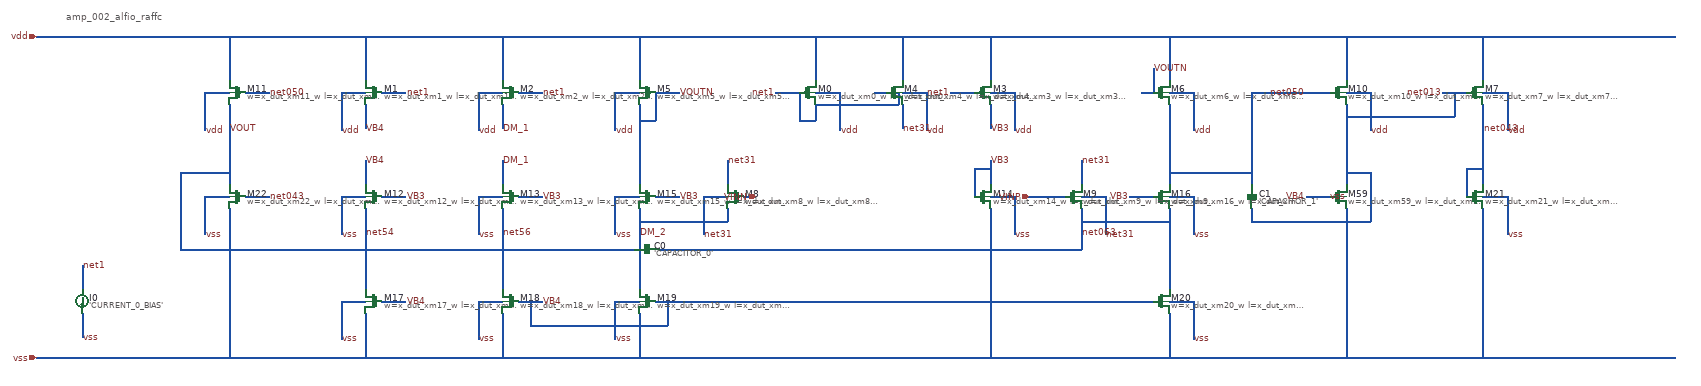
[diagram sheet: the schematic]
v {xschem version=3.4.6 file_version=1.2}
G {}
K {}
V {}
S {}
E {}
T {amp_002_alfio_raffc} -1785 -200 0 0 0.4 0.4 {}
C {devices/capa_np.sym} -340 390 1 0 {name=C0 value='CAPACITOR_0'}
C {devices/capa_np.sym} 1165 260 0 0 {name=C1 value='CAPACITOR_1'}
C {devices/isource_np.sym} -1745 520 0 0 {name=I0 value='CURRENT_0_BIAS'}
C {devices/sg13_lv_pmos_np.sym} 60 0 0 0 {name=M0 model=sg13_lv_pmos spiceprefix=X w=x_dut_xm0_w l=x_dut_xm0_l m=x_dut_xm0_m}
C {devices/sg13_lv_pmos_np.sym} -1020 0 0 1 {name=M1 model=sg13_lv_pmos spiceprefix=X w=x_dut_xm1_w l=x_dut_xm1_l m=x_dut_xm1_m}
C {devices/sg13_lv_pmos_np.sym} 1380 0 0 0 {name=M10 model=sg13_lv_pmos spiceprefix=X w=x_dut_xm10_w l=x_dut_xm10_l m=x_dut_xm10_m}
C {devices/sg13_lv_pmos_np.sym} -1360 0 0 1 {name=M11 model=sg13_lv_pmos spiceprefix=X w=x_dut_xm11_w l=x_dut_xm11_l m=x_dut_xm11_m}
C {devices/sg13_lv_nmos_np.sym} -1020 260 0 1 {name=M12 model=sg13_lv_nmos spiceprefix=X w=x_dut_xm12_w l=x_dut_xm12_l m=x_dut_xm12_m}
C {devices/sg13_lv_nmos_np.sym} -680 260 0 1 {name=M13 model=sg13_lv_nmos spiceprefix=X w=x_dut_xm13_w l=x_dut_xm13_l m=x_dut_xm13_m}
C {devices/sg13_lv_nmos_np.sym} 495 260 0 0 {name=M14 model=sg13_lv_nmos spiceprefix=X w=x_dut_xm14_w l=x_dut_xm14_l m=x_dut_xm14_m}
C {devices/sg13_lv_nmos_np.sym} -340 260 0 1 {name=M15 model=sg13_lv_nmos spiceprefix=X w=x_dut_xm15_w l=x_dut_xm15_l m=x_dut_xm15_m}
C {devices/sg13_lv_nmos_np.sym} 940 260 0 0 {name=M16 model=sg13_lv_nmos spiceprefix=X w=x_dut_xm16_w l=x_dut_xm16_l m=x_dut_xm16_m}
C {devices/sg13_lv_nmos_np.sym} -1020 520 0 1 {name=M17 model=sg13_lv_nmos spiceprefix=X w=x_dut_xm17_w l=x_dut_xm17_l m=x_dut_xm17_m}
C {devices/sg13_lv_nmos_np.sym} -680 520 0 1 {name=M18 model=sg13_lv_nmos spiceprefix=X w=x_dut_xm18_w l=x_dut_xm18_l m=x_dut_xm18_m}
C {devices/sg13_lv_nmos_np.sym} -340 520 0 1 {name=M19 model=sg13_lv_nmos spiceprefix=X w=x_dut_xm19_w l=x_dut_xm19_l m=x_dut_xm19_m}
C {devices/sg13_lv_pmos_np.sym} -680 0 0 1 {name=M2 model=sg13_lv_pmos spiceprefix=X w=x_dut_xm2_w l=x_dut_xm2_l m=x_dut_xm2_m}
C {devices/sg13_lv_nmos_np.sym} 940 520 0 0 {name=M20 model=sg13_lv_nmos spiceprefix=X w=x_dut_xm20_w l=x_dut_xm20_l m=x_dut_xm20_m}
C {devices/sg13_lv_nmos_np.sym} 1720 260 0 0 {name=M21 model=sg13_lv_nmos spiceprefix=X w=x_dut_xm21_w l=x_dut_xm21_l m=x_dut_xm21_m}
C {devices/sg13_lv_nmos_np.sym} -1360 260 0 1 {name=M22 model=sg13_lv_nmos spiceprefix=X w=x_dut_xm22_w l=x_dut_xm22_l m=x_dut_xm22_m}
C {devices/sg13_lv_pmos_np.sym} 495 0 0 0 {name=M3 model=sg13_lv_pmos spiceprefix=X w=x_dut_xm3_w l=x_dut_xm3_l m=x_dut_xm3_m}
C {devices/sg13_lv_pmos_np.sym} 275 0 0 0 {name=M4 model=sg13_lv_pmos spiceprefix=X w=x_dut_xm4_w l=x_dut_xm4_l m=x_dut_xm4_m}
C {devices/sg13_lv_pmos_np.sym} -340 0 0 1 {name=M5 model=sg13_lv_pmos spiceprefix=X w=x_dut_xm5_w l=x_dut_xm5_l m=x_dut_xm5_m}
C {devices/sg13_lv_nmos_np.sym} 1380 260 0 0 {name=M59 model=sg13_lv_nmos spiceprefix=X w=x_dut_xm59_w l=x_dut_xm59_l m=x_dut_xm59_m}
C {devices/sg13_lv_pmos_np.sym} 940 0 0 0 {name=M6 model=sg13_lv_pmos spiceprefix=X w=x_dut_xm6_w l=x_dut_xm6_l m=x_dut_xm6_m}
C {devices/sg13_lv_pmos_np.sym} 1720 0 0 0 {name=M7 model=sg13_lv_pmos spiceprefix=X w=x_dut_xm7_w l=x_dut_xm7_l m=x_dut_xm7_m}
C {devices/sg13_lv_pmos_np.sym} -120 260 0 1 {name=M8 model=sg13_lv_pmos spiceprefix=X w=x_dut_xm8_w l=x_dut_xm8_l m=x_dut_xm8_m}
C {devices/sg13_lv_pmos_np.sym} 720 260 0 0 {name=M9 model=sg13_lv_pmos spiceprefix=X w=x_dut_xm9_w l=x_dut_xm9_l m=x_dut_xm9_m}
N -1745 430 -1745 490 {}
N -1745 550 -1745 610 {}
N -1500 200 -1500 390 {}
N -1440 0 -1440 94 {}
N -1440 260 -1440 354 {}
N -1380 -140 -1380 -30 {}
N -1380 30 -1380 230 {}
N -1380 290 -1380 660 {}
N -1100 0 -1100 94 {}
N -1100 260 -1100 354 {}
N -1100 520 -1100 614 {}
N -1040 -140 -1040 -30 {}
N -1040 30 -1040 90 {}
N -1040 170 -1040 230 {}
N -1040 290 -1040 490 {}
N -1040 550 -1040 660 {}
N -760 0 -760 94 {}
N -760 260 -760 354 {}
N -760 520 -760 614 {}
N -700 -140 -700 -30 {}
N -700 30 -700 90 {}
N -700 170 -700 230 {}
N -700 290 -700 490 {}
N -700 550 -700 660 {}
N -630 520 -630 580 {}
N -420 0 -420 94 {}
N -420 260 -420 354 {}
N -420 520 -420 614 {}
N -360 -140 -360 -30 {}
N -360 30 -360 230 {}
N -360 290 -360 490 {}
N -360 550 -360 660 {}
N -320 0 -320 70 {}
N -290 520 -290 580 {}
N -200 260 -200 354 {}
N -140 170 -140 230 {}
N -140 290 -140 320 {}
N 40 0 40 70 {}
N 80 -140 80 -30 {}
N 80 30 80 70 {}
N 140 0 140 94 {}
N 285 0 285 30 {}
N 295 -140 295 -30 {}
N 295 30 295 90 {}
N 355 0 355 94 {}
N 475 190 475 260 {}
N 515 -140 515 -30 {}
N 515 30 515 90 {}
N 515 170 515 230 {}
N 515 290 515 660 {}
N 575 0 575 94 {}
N 575 260 575 354 {}
N 740 170 740 230 {}
N 740 290 740 390 {}
N 800 260 800 354 {}
N 920 -60 920 0 {}
N 960 -140 960 -30 {}
N 960 30 960 230 {}
N 960 290 960 490 {}
N 960 550 960 660 {}
N 1020 0 1020 94 {}
N 1020 260 1020 354 {}
N 1020 520 1020 614 {}
N 1165 0 1165 230 {}
N 1165 290 1165 320 {}
N 1400 -140 1400 -30 {}
N 1400 30 1400 230 {}
N 1400 290 1400 660 {}
N 1460 0 1460 94 {}
N 1460 200 1460 320 {}
N 1670 0 1670 60 {}
N 1700 190 1700 260 {}
N 1740 -140 1740 -30 {}
N 1740 30 1740 230 {}
N 1740 290 1740 660 {}
N 1800 0 1800 94 {}
N 1800 260 1800 354 {}
N -1860 -140 2220 -140 {}
N -1440 0 -1380 0 {}
N -1340 0 -1280 0 {}
N -1100 0 -1040 0 {}
N -1000 0 -940 0 {}
N -760 0 -700 0 {}
N -660 0 -600 0 {}
N -420 0 -360 0 {}
N -320 0 -260 0 {}
N -20 0 40 0 {}
N 80 0 140 0 {}
N 225 0 285 0 {}
N 295 0 355 0 {}
N 415 0 475 0 {}
N 515 0 575 0 {}
N 890 0 920 0 {}
N 960 0 1020 0 {}
N 1165 0 1360 0 {}
N 1400 0 1460 0 {}
N 1640 0 1700 0 {}
N 1740 0 1800 0 {}
N 80 30 285 30 {}
N 1400 60 1670 60 {}
N -360 70 -320 70 {}
N 40 70 80 70 {}
N 475 190 515 190 {}
N 1700 190 1740 190 {}
N -1500 200 -1380 200 {}
N 960 200 1165 200 {}
N 1400 200 1460 200 {}
N -1440 260 -1380 260 {}
N -1340 260 -1280 260 {}
N -1100 260 -1040 260 {}
N -1000 260 -940 260 {}
N -760 260 -700 260 {}
N -660 260 -600 260 {}
N -420 260 -360 260 {}
N -320 260 -260 260 {}
N -200 260 -140 260 {}
N -100 260 -70 260 {}
N 515 260 575 260 {}
N 610 260 700 260 {}
N 740 260 800 260 {}
N 860 260 920 260 {}
N 960 260 1020 260 {}
N 1300 260 1360 260 {}
N 1740 260 1800 260 {}
N -360 320 -140 320 {}
N 740 320 960 320 {}
N 1165 320 1460 320 {}
N -1500 390 -370 390 {}
N -310 390 740 390 {}
N -1100 520 -1040 520 {}
N -1000 520 -940 520 {}
N -760 520 -700 520 {}
N -660 520 -600 520 {}
N -420 520 -360 520 {}
N -320 520 920 520 {}
N 960 520 1020 520 {}
N -630 580 -290 580 {}
N -1860 660 2220 660 {}
C {devices/lab_wire.sym} -700 90 2 0 {name=l0 lab=DM_1}
C {devices/lab_wire.sym} -700 170 0 1 {name=l1 lab=DM_1}
C {devices/lab_wire.sym} -360 350 2 0 {name=l2 lab=DM_2}
C {devices/lab_wire.sym} -940 260 0 1 {name=l3 lab=VB3}
C {devices/lab_wire.sym} -600 260 0 1 {name=l4 lab=VB3}
C {devices/lab_wire.sym} -260 260 0 1 {name=l5 lab=VB3}
C {devices/lab_wire.sym} 515 170 0 1 {name=l6 lab=VB3}
C {devices/lab_wire.sym} 515 90 2 0 {name=l7 lab=VB3}
C {devices/lab_wire.sym} 860 260 0 0 {name=l8 lab=VB3}
C {devices/lab_wire.sym} -1040 90 2 0 {name=l9 lab=VB4}
C {devices/lab_wire.sym} -1040 170 0 1 {name=l10 lab=VB4}
C {devices/lab_wire.sym} -940 520 0 1 {name=l11 lab=VB4}
C {devices/lab_wire.sym} -600 520 0 1 {name=l12 lab=VB4}
C {devices/lab_wire.sym} 1300 260 0 0 {name=l13 lab=VB4}
C {devices/lab_wire.sym} -1380 90 2 0 {name=l14 lab=VOUT}
C {devices/lab_wire.sym} -260 0 0 1 {name=l15 lab=VOUTN}
C {devices/lab_wire.sym} 920 -60 0 1 {name=l16 lab=VOUTN}
C {devices/lab_wire.sym} 1640 0 0 0 {name=l17 lab=net013}
C {devices/lab_wire.sym} -1280 260 0 1 {name=l18 lab=net043}
C {devices/lab_wire.sym} 1740 90 2 0 {name=l19 lab=net043}
C {devices/lab_wire.sym} -1280 0 0 1 {name=l20 lab=net050}
C {devices/lab_wire.sym} 1300 0 0 0 {name=l21 lab=net050}
C {devices/lab_wire.sym} 740 350 2 0 {name=l22 lab=net063}
C {devices/lab_wire.sym} -940 0 0 1 {name=l23 lab=net1}
C {devices/lab_wire.sym} -600 0 0 1 {name=l24 lab=net1}
C {devices/lab_wire.sym} -20 0 0 0 {name=l25 lab=net1}
C {devices/lab_wire.sym} 415 0 0 0 {name=l26 lab=net1}
C {devices/lab_wire.sym} -140 170 0 1 {name=l27 lab=net31}
C {devices/lab_wire.sym} 295 90 2 0 {name=l28 lab=net31}
C {devices/lab_wire.sym} 740 170 0 1 {name=l29 lab=net31}
C {devices/lab_wire.sym} -1040 350 2 0 {name=l30 lab=net54}
C {devices/lab_wire.sym} -700 350 2 0 {name=l31 lab=net56}
C {devices/lab_wire.sym} -200 354 2 0 {name=l32 lab=net31}
C {devices/lab_wire.sym} 800 354 2 0 {name=l33 lab=net31}
C {devices/lab_wire.sym} 140 94 2 0 {name=l34 lab=vdd}
C {devices/lab_wire.sym} -1100 94 2 0 {name=l35 lab=vdd}
C {devices/lab_wire.sym} 1460 94 2 0 {name=l36 lab=vdd}
C {devices/lab_wire.sym} -1440 94 2 0 {name=l37 lab=vdd}
C {devices/lab_wire.sym} -760 94 2 0 {name=l38 lab=vdd}
C {devices/lab_wire.sym} 575 94 2 0 {name=l39 lab=vdd}
C {devices/lab_wire.sym} 355 94 2 0 {name=l40 lab=vdd}
C {devices/lab_wire.sym} -420 94 2 0 {name=l41 lab=vdd}
C {devices/lab_wire.sym} 1020 94 2 0 {name=l42 lab=vdd}
C {devices/lab_wire.sym} 1800 94 2 0 {name=l43 lab=vdd}
C {devices/lab_wire.sym} -1100 354 2 0 {name=l44 lab=vss}
C {devices/lab_wire.sym} -760 354 2 0 {name=l45 lab=vss}
C {devices/lab_wire.sym} 575 354 2 0 {name=l46 lab=vss}
C {devices/lab_wire.sym} -420 354 2 0 {name=l47 lab=vss}
C {devices/lab_wire.sym} 1020 354 2 0 {name=l48 lab=vss}
C {devices/lab_wire.sym} -1100 614 2 0 {name=l49 lab=vss}
C {devices/lab_wire.sym} -760 614 2 0 {name=l50 lab=vss}
C {devices/lab_wire.sym} -420 614 2 0 {name=l51 lab=vss}
C {devices/lab_wire.sym} 1020 614 2 0 {name=l52 lab=vss}
C {devices/lab_wire.sym} 1800 354 2 0 {name=l53 lab=vss}
C {devices/lab_wire.sym} -1440 354 2 0 {name=l54 lab=vss}
C {devices/lab_wire.sym} 1400 260 0 0 {name=l55 lab=vss}
C {devices/lab_wire.sym} -1745 430 0 1 {name=l56 lab=net1}
C {devices/lab_wire.sym} -1745 610 2 0 {name=l57 lab=vss}
C {devices/ipin.sym} -70 260 0 0 {name=p0 lab=VINN}
C {devices/ipin.sym} 610 260 0 0 {name=p1 lab=VINP}
C {devices/iopin.sym} -1860 -140 0 0 {name=p2 lab=vdd}
C {devices/iopin.sym} -1860 660 0 0 {name=p3 lab=vss}
